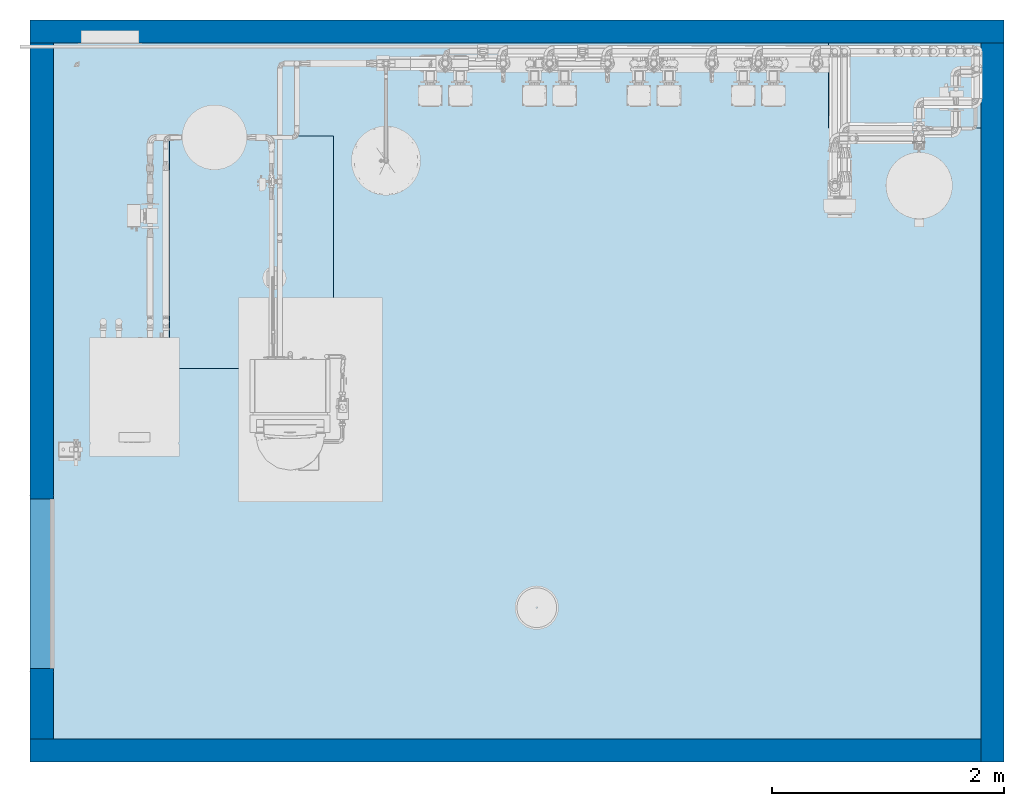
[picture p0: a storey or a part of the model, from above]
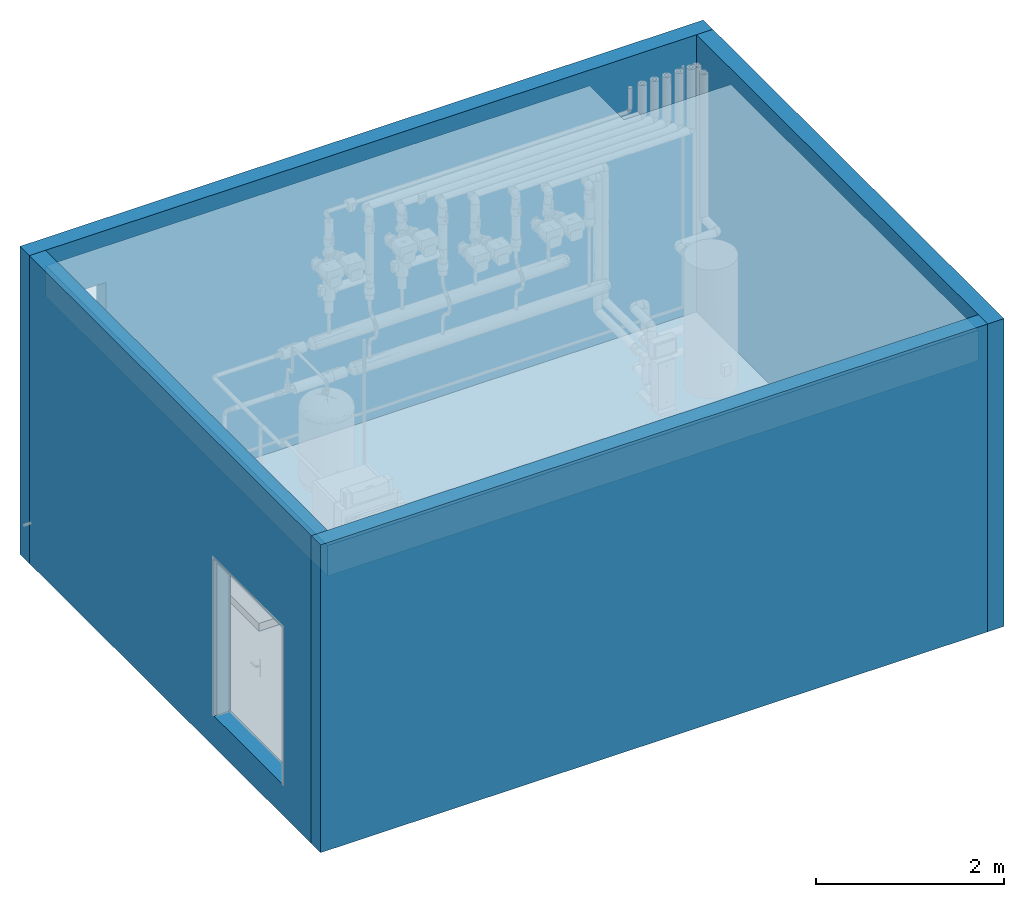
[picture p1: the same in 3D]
Properties of the parts of a building model (IFC2X3)

# File
Description: ViewDefinition [CoordinationView_V2.0], RevitIdentifiers [VersionGUID: c51af800-4d1c-406b-a257-0cf0d2222cb8, NumberOfSaves: 71], CoordinateReference [CoordinateBase: Coordonnées partagées]
File name: 0001
Time: 2023-06-20T16:45:23+01:00
Written by: ODA SDAI 23.12
Made in: Autodesk Revit 24.0.5.432 (FRA) - IFC 24.0.5.432

# IfcProject, 0001
LongName: Chaufferie REVIT MEP; Phase: Etat du projet

# IfcSite, Default
RefLatitude: 48, 51, 23, 807373; RefLongitude: 2, 21, 7, 999076; RefElevation: 0 mm

# IfcBuilding
Pset_BuildingCommon - NumberOfStoreys: 2

# IfcBuildingStorey: Niveau:Pointe 8 mm (2)
Name | LongName | Elevation (mm)
Niveau 0 | Niveau 0 | 0
Niveau 1 | Niveau 1 | 3000

# IfcBuildingElementProxy: Ballon d'eau chaude - 150-300 L test:300 L, Ballon d'eau chaude - 150-300 L test:300 L:723451
In: Niveau 0
Type - Material: <Unnamed>
Pset_BuildingElementProxyCommon - Reference: 300 L; sets with these values: 2
Group: Chauffage aller 2; Chauffage retour 3; Eau Froide Sanitaire 1

# IfcBuildingElementProxy: Collecteurs:Type 1, Collecteurs:Type 1:725838
In: Niveau 0
Type - Material: <Unnamed>
Pset_BuildingElementProxyCommon - Reference: Type 1; sets with these values: 2
Group: Chauffage aller 2; Chauffage aller 4; Chauffage aller 8; Chauffage aller 9; Chauffage aller 1; Chauffage aller 10; Chauffage retour 1; Chauffage aller 11

# IfcBuildingElementProxy: Echangeur de chaleur - Plaques:Standard, Echangeur de chaleur - Plaques:Standard:722448
In: Niveau 0
Type - Material: <Unnamed>
Pset_BuildingElementProxyCommon - Reference: Standard; sets with these values: 2
Group: Chauffage retour 2; Chauffage aller 16; Chauffage aller 2

# IfcBuildingElementProxy: Gaz naturel – Compteur:Compteur gaz G4, Gaz naturel – Compteur:Compteur gaz G4:987432
In: Niveau 0
Type - Material: GRDF Gris, GRDF Blanc, GRDF Jaune, <Unnamed>
Pset_BuildingElementProxyCommon - Reference: Compteur gaz G4; sets with these values: 2
Group: Chauffage retour 7

# IfcBuildingElementProxy: Vase d'expansion:Vase d'expansion, Vase d'expansion:Vase d'expansion:720942
In: Niveau 0
Type - Material: Smooth - Red
Type - Pset_ManufacturerTypeInformation - ArticleNumber: 16301; Manufacturer: Flamco B.V.
Pset_BuildingElementProxyCommon - Reference: Vase d'expansion; sets with these values: 2
Group: Autre 1

# IfcBuildingElementProxy: Viessmann_Vitocal 300-G:BW 301.A29, Viessmann_Vitocal 300-G:BW 301.A29:902832
In: Niveau 0
Type - Material: Color RGB 165-165-165, Color RGB 30-30-30, Color RGB 254-0-0
Type - Pset_ManufacturerTypeInformation - Manufacturer: Viessmann
Type - Pset_ProvisionForVoid - Width: 1086 mm; Height: 1074 mm
Pset_BuildingElementProxyCommon - Reference: BW 301.A29; sets with these values: 2
Group: Chauffage aller 1; Chauffage retour 11; Chauffage aller 5; Chauffage retour 5

# IfcCovering: Isolation des canalisations:Laine minérale (145)
PredefinedType: INSULATION; Material: Isolation - Laine minérale
Pset_CoveringCommon - Reference: Laine minérale; sets with these values: 2
Name (Isolation des canalisations:Laine minérale:...) | In
881231 | Niveau 0
881232 | Niveau 0
881244 | Niveau 0
881245 | Niveau 0
881246 | Niveau 0
881247 | Niveau 0
881248 | Niveau 0
881249 | Niveau 0
881250 | Niveau 0
881251 | Niveau 0
881252 | Niveau 0
881254 | Niveau 0
881255 | Niveau 0
881256 | Niveau 0
881257 | Niveau 0
881258 | Niveau 0
881259 | Niveau 0
881260 | Niveau 0
881261 | Niveau 0
881262 | Niveau 0
881263 | Niveau 0
881264 | Niveau 0
881278 | Niveau 1
881279 | Niveau 1
881280 | Niveau 1
881281 | Niveau 1
881282 | Niveau 1
881283 | Niveau 0
881284 | Niveau 1
881285 | Niveau 0
881286 | Niveau 0
881287 | Niveau 0
881288 | Niveau 1
881297 | Niveau 0
881298 | Niveau 0
881299 | Niveau 0
881300 | Niveau 0
881301 | Niveau 0
881302 | Niveau 0
881304 | Niveau 0
881305 | Niveau 0
881306 | Niveau 0
881307 | Niveau 0
881308 | Niveau 0
881309 | Niveau 0
881310 | Niveau 0
881312 | Niveau 0
881313 | Niveau 0
881320 | Niveau 0
881321 | Niveau 0
881331 | Niveau 0
881332 | Niveau 0
881333 | Niveau 0
881334 | Niveau 0
881335 | Niveau 0
881336 | Niveau 0
881337 | Niveau 0
881338 | Niveau 0
881339 | Niveau 0
881340 | Niveau 0
881341 | Niveau 0
881342 | Niveau 0
881343 | Niveau 0
881344 | Niveau 0
881345 | Niveau 0
881346 | Niveau 0
881347 | Niveau 0
881348 | Niveau 0
881349 | Niveau 0
881350 | Niveau 0
881351 | Niveau 0
881352 | Niveau 0
881353 | Niveau 0
881354 | Niveau 0
881355 | Niveau 0
881356 | Niveau 0
881357 | Niveau 0
881358 | Niveau 0
881359 | Niveau 0
881360 | Niveau 0
881361 | Niveau 0
881362 | Niveau 0
881363 | Niveau 0
881364 | Niveau 0
881365 | Niveau 0
881366 | Niveau 0
881367 | Niveau 0
881368 | Niveau 0
881369 | Niveau 0
881370 | Niveau 0
881371 | Niveau 0
881372 | Niveau 0
881373 | Niveau 0
881374 | Niveau 0
881375 | Niveau 0
881376 | Niveau 0
881377 | Niveau 0
881378 | Niveau 0
881379 | Niveau 0
881380 | Niveau 0
881381 | Niveau 0
881382 | Niveau 0
881383 | Niveau 0
881384 | Niveau 0
881385 | Niveau 0
881386 | Niveau 0
881387 | Niveau 0
881388 | Niveau 0
881389 | Niveau 0
881390 | Niveau 0
881391 | Niveau 0
881392 | Niveau 0
881393 | Niveau 0
881394 | Niveau 0
881395 | Niveau 0
881396 | Niveau 0
881397 | Niveau 0
881398 | Niveau 0
881399 | Niveau 0
881400 | Niveau 0
881401 | Niveau 0
881402 | Niveau 0
881403 | Niveau 0
881404 | Niveau 0
881405 | Niveau 0
881406 | Niveau 0
881409 | Niveau 0
881410 | Niveau 0
881411 | Niveau 0
881412 | Niveau 0
881413 | Niveau 0
881414 | Niveau 0
881434 | Niveau 0
881435 | Niveau 0
881436 | Niveau 0
881437 | Niveau 0
881438 | Niveau 0
881439 | Niveau 0
881440 | Niveau 0
881441 | Niveau 0
881442 | Niveau 0
881443 | Niveau 0
881444 | Niveau 0
881453 | Niveau 0
881454 | Niveau 0

# IfcDistributionPort (621)
Description: Flow
Name | FlowDirection | Group
InPort_720942_1 | SINK | Autre 1
OutPort_934051_2 | SOURCE | Autre 1
InPort_732593_1 | SINK | Chauffage retour 2
OutPort_722448_2 | SOURCE | Chauffage retour 2
InPort_722448_4 | SINK | Chauffage aller 16
OutPort_734984_1 | SOURCE | Chauffage aller 16
Port_722448_5 | SOURCEANDSINK
InPort_836824_1 | SINK | Chauffage aller 16
OutPort_722448_6 | SOURCE | Chauffage aller 16
InPort_722448_7 | SINK | Chauffage aller 2
OutPort_734946_1 | SOURCE | Chauffage aller 2
OutPort_723451_1 | SOURCE
InPort_723451_2 | SINK | Chauffage aller 2
OutPort_825239_0 | SOURCE | Chauffage aller 2
OutPort_723451_3 | SOURCE | Chauffage retour 3
InPort_723451_4 | SINK | Eau Froide Sanitaire 1
OutPort_824245_1 | SOURCE | Eau Froide Sanitaire 1
Port_723451_5 | SOURCEANDSINK
Port_725838_5 | SOURCEANDSINK | Chauffage aller 4
Port_789472_1 | SOURCEANDSINK | Chauffage aller 4
Port_725838_7 | SOURCEANDSINK | Chauffage aller 8
Port_789541_1 | SOURCEANDSINK | Chauffage aller 8
Port_725838_9 | SOURCEANDSINK | Chauffage aller 9
Port_789702_1 | SOURCEANDSINK | Chauffage aller 9
Port_725838_11 | SOURCEANDSINK | Chauffage aller 2
Port_789725_1 | SOURCEANDSINK | Chauffage aller 2
InPort_725838_13 | SINK | Chauffage aller 1
OutPort_813002_0 | SOURCE | Chauffage aller 1
Port_725838_14 | SOURCEANDSINK | Chauffage aller 4
Port_731198_1 | SOURCEANDSINK | Chauffage aller 4
Port_725838_15 | SOURCEANDSINK | Chauffage aller 8
Port_788116_1 | SOURCEANDSINK | Chauffage aller 8
Port_725838_16 | SOURCEANDSINK | Chauffage aller 10
Port_731342_1 | SOURCEANDSINK | Chauffage aller 10
InPort_725838_18 | SINK | Chauffage retour 1
OutPort_812962_0 | SOURCE | Chauffage retour 1
InPort_731486_1 | SINK | Chauffage aller 11
OutPort_725838_19 | SOURCE | Chauffage aller 11
Port_730939_0 | SOURCEANDSINK | Chauffage aller 12
Port_777958_1 | SOURCEANDSINK | Chauffage aller 12
Port_730939_1 | SOURCEANDSINK | Chauffage aller 12
Port_732698_2 | SOURCEANDSINK | Chauffage aller 12
Port_730962_0 | SOURCEANDSINK | Chauffage aller 12
Port_880787_2 | SOURCEANDSINK | Chauffage aller 12
Port_730962_1 | SOURCEANDSINK | Chauffage aller 12
Port_732700_2 | SOURCEANDSINK | Chauffage aller 12
Port_731057_0 | SOURCEANDSINK | Chauffage aller 12
Port_732700_1 | SOURCEANDSINK | Chauffage aller 12
Port_731057_1 | SOURCEANDSINK | Chauffage aller 12
Port_731196_0 | SOURCEANDSINK | Chauffage aller 4
Port_784621_1 | SOURCEANDSINK | Chauffage aller 4
Port_731196_1 | SOURCEANDSINK | Chauffage aller 4
Port_731204_2 | SOURCEANDSINK | Chauffage aller 4
Port_731198_0 | SOURCEANDSINK | Chauffage aller 4
Port_877798_1 | SOURCEANDSINK | Chauffage aller 4
Port_731202_0 | SOURCEANDSINK | Chauffage aller 4
Port_731204_1 | SOURCEANDSINK | Chauffage aller 4
Port_731202_1 | SOURCEANDSINK | Chauffage aller 4
Port_731210_1 | SOURCEANDSINK | Chauffage aller 4
Port_731208_0 | SOURCEANDSINK | Chauffage aller 4
Port_731210_2 | SOURCEANDSINK | Chauffage aller 4
Port_731208_1 | SOURCEANDSINK | Chauffage aller 4
Port_731294_0 | SOURCEANDSINK | Chauffage aller 13
Port_788303_1 | SOURCEANDSINK | Chauffage aller 13
Port_731294_1 | SOURCEANDSINK | Chauffage aller 13
Port_731651_2 | SOURCEANDSINK | Chauffage aller 13
Port_731300_0 | SOURCEANDSINK | Chauffage aller 13
Port_880819_2 | SOURCEANDSINK | Chauffage aller 13
Port_731300_1 | SOURCEANDSINK | Chauffage aller 13
Port_731653_2 | SOURCEANDSINK | Chauffage aller 13
Port_731318_0 | SOURCEANDSINK | Chauffage aller 8
Port_788230_1 | SOURCEANDSINK | Chauffage aller 8
Port_731318_1 | SOURCEANDSINK | Chauffage aller 8
Port_731695_2 | SOURCEANDSINK | Chauffage aller 8
Port_731324_0 | SOURCEANDSINK | Chauffage aller 8
Port_731695_1 | SOURCEANDSINK | Chauffage aller 8
Port_731324_1 | SOURCEANDSINK | Chauffage aller 8
Port_731697_2 | SOURCEANDSINK | Chauffage aller 8
Port_731340_0 | SOURCEANDSINK | Chauffage aller 10
Port_791255_1 | SOURCEANDSINK | Chauffage aller 10
Port_731340_1 | SOURCEANDSINK | Chauffage aller 10
Port_731843_2 | SOURCEANDSINK | Chauffage aller 10
Port_731342_0 | SOURCEANDSINK | Chauffage aller 10
Port_877814_1 | SOURCEANDSINK | Chauffage aller 10
Port_731346_0 | SOURCEANDSINK | Chauffage aller 10
Port_731843_1 | SOURCEANDSINK | Chauffage aller 10
Port_731346_1 | SOURCEANDSINK | Chauffage aller 10
Port_731845_2 | SOURCEANDSINK | Chauffage aller 10
Port_731430_0 | SOURCEANDSINK | Chauffage aller 14
Port_788510_1 | SOURCEANDSINK | Chauffage aller 14
Port_731430_1 | SOURCEANDSINK | Chauffage aller 14
Port_731759_2 | SOURCEANDSINK | Chauffage aller 14
Port_731436_0 | SOURCEANDSINK | Chauffage aller 14
Port_731759_1 | SOURCEANDSINK | Chauffage aller 14
Port_731436_1 | SOURCEANDSINK | Chauffage aller 14
Port_731761_2 | SOURCEANDSINK | Chauffage aller 14
InPort_731458_0 | SINK | Chauffage aller 2
OutPort_789825_1 | SOURCE | Chauffage aller 2
InPort_731466_2 | SINK | Chauffage aller 2
OutPort_731458_1 | SOURCE | Chauffage aller 2
InPort_800652_1 | SINK | Chauffage aller 2
OutPort_731460_0 | SOURCE | Chauffage aller 2
InPort_731460_1 | SINK | Chauffage aller 2
InPort_732428_0 | SINK | Chauffage aller 2
OutPort_731466_1 | SOURCE | Chauffage aller 2
InPort_731484_0 | SINK | Chauffage aller 11
OutPort_791313_1 | SOURCE | Chauffage aller 11
InPort_731492_2 | SINK | Chauffage aller 11
OutPort_731484_1 | SOURCE | Chauffage aller 11
InPort_877834_1 | SINK | Chauffage aller 11
OutPort_731486_0 | SOURCE | Chauffage aller 11
InPort_732634_0 | SINK | Chauffage aller 11
OutPort_731492_1 | SOURCE | Chauffage aller 11
Port_731572_0 | SOURCEANDSINK | Chauffage aller 13
Port_731653_1 | SOURCEANDSINK | Chauffage aller 13
Port_731572_1 | SOURCEANDSINK | Chauffage aller 13
Port_731586_0 | SOURCEANDSINK | Chauffage aller 8
Port_731697_1 | SOURCEANDSINK | Chauffage aller 8
Port_731586_1 | SOURCEANDSINK | Chauffage aller 8
Port_731600_0 | SOURCEANDSINK | Chauffage aller 14
Port_731761_1 | SOURCEANDSINK | Chauffage aller 14
Port_731600_1 | SOURCEANDSINK | Chauffage aller 14
Port_731651_1 | SOURCEANDSINK | Chauffage aller 13
Port_880821_0 | SOURCEANDSINK | Chauffage aller 13
Port_731790_0 | SOURCEANDSINK | Chauffage aller 10
Port_731845_1 | SOURCEANDSINK | Chauffage aller 10
Port_731790_1 | SOURCEANDSINK | Chauffage aller 10
InPort_734948_1 | SINK | Chauffage aller 2
OutPort_732251_0 | SOURCE | Chauffage aller 2
InPort_732251_1 | SINK | Chauffage aller 2
OutPort_732496_2 | SOURCE | Chauffage aller 2
InPort_732496_1 | SINK | Chauffage aller 2
OutPort_732428_1 | SOURCE | Chauffage aller 2
InPort_732518_0 | SINK | Chauffage retour 2
OutPort_732593_2 | SOURCE | Chauffage retour 2
InPort_809786_1 | SINK | Chauffage retour 2
OutPort_732518_1 | SOURCE | Chauffage retour 2
InPort_809790_1 | SINK | Chauffage aller 11
OutPort_732634_1 | SOURCE | Chauffage aller 11
Port_732698_1 | SOURCEANDSINK | Chauffage aller 12
Port_880789_0 | SOURCEANDSINK | Chauffage aller 12
Port_734033_0 | SOURCEANDSINK | Chauffage aller 16
Port_836876_3 | SOURCEANDSINK | Chauffage aller 16
Port_734033_1 | SOURCEANDSINK | Chauffage aller 16
Port_836287_3 | SOURCEANDSINK | Chauffage aller 16
InPort_734276_0 | SINK | Chauffage retour 4
OutPort_824275_2 | SOURCE | Chauffage retour 4
InPort_824307_2 | SINK | Eau Froide Sanitaire 1
OutPort_734276_1 | SOURCE | Eau Froide Sanitaire 1
Port_734457_0 | SOURCEANDSINK | Autre 1
Port_934110_2 | SOURCEANDSINK | Autre 1
Port_734457_1 | SOURCEANDSINK | Autre 1
Port_934114_2 | SOURCEANDSINK | Autre 1
Port_734536_0 | SOURCEANDSINK | Autre 1
Port_934110_1 | SOURCEANDSINK | Autre 1
Port_734536_1 | SOURCEANDSINK | Autre 1
Port_789916_1 | SOURCEANDSINK | Autre 1
Port_734538_1 | SOURCEANDSINK | Chauffage retour 1
InPort_734539_1 | SINK | Chauffage retour 1
OutPort_734538_2 | SOURCE | Chauffage retour 1
InPort_734538_3 | SINK | Chauffage retour 1
OutPort_869441_1 | SOURCE | Chauffage retour 1
InPort_812960_1 | SINK | Chauffage retour 1
OutPort_734539_0 | SOURCE | Chauffage retour 1
InPort_734986_1 | SINK | Chauffage aller 16
OutPort_734875_0 | SOURCE | Chauffage aller 16
InPort_734875_1 | SINK | Chauffage aller 16
OutPort_836876_1 | SOURCE | Chauffage aller 16
InPort_734946_2 | SINK | Chauffage aller 2
OutPort_734887_0 | SOURCE | Chauffage aller 2
InPort_734887_1 | SINK | Chauffage aller 2
OutPort_734948_2 | SOURCE | Chauffage aller 2
InPort_734984_2 | SINK | Chauffage aller 16
OutPort_734972_0 | SOURCE | Chauffage aller 16
InPort_734972_1 | SINK | Chauffage aller 16
OutPort_734986_2 | SOURCE | Chauffage aller 16
Port_761970_4 | SOURCEANDSINK | Chauffage aller 4
Port_789420_1 | SOURCEANDSINK | Chauffage aller 4
Port_761970_5 | SOURCEANDSINK
Port_761970_6 | SOURCEANDSINK
Port_761970_7 | SOURCEANDSINK | Chauffage aller 4
Port_761970_8 | SOURCEANDSINK | Chauffage aller 4
Port_777889_0 | SOURCEANDSINK | Chauffage aller 12
Port_800542_2 | SOURCEANDSINK | Chauffage aller 12
Port_777889_1 | SOURCEANDSINK | Chauffage aller 12
Port_777958_2 | SOURCEANDSINK | Chauffage aller 12
Port_784621_2 | SOURCEANDSINK | Chauffage aller 4
Port_800558_0 | SOURCEANDSINK | Chauffage aller 4
Port_784664_1 | SOURCEANDSINK | Chauffage aller 4
Port_789472_0 | SOURCEANDSINK | Chauffage aller 4
Port_784664_2 | SOURCEANDSINK | Chauffage aller 4
Port_789420_0 | SOURCEANDSINK | Chauffage aller 4
InPort_788051_1 | SINK | Chauffage aller 4
OutPort_784664_3 | SOURCE | Chauffage aller 4
Port_784664_4 | SOURCEANDSINK
InPort_788062_3 | SINK | Chauffage aller 4
OutPort_788051_0 | SOURCE | Chauffage aller 4
Port_788062_1 | SOURCEANDSINK | Chauffage aller 4
Port_877800_0 | SOURCEANDSINK | Chauffage aller 4
Port_788062_2 | SOURCEANDSINK | Chauffage aller 4
Port_788063_1 | SOURCEANDSINK | Chauffage aller 4
Port_788063_0 | SOURCEANDSINK | Chauffage aller 4
Port_800556_1 | SOURCEANDSINK | Chauffage aller 4
Port_788116_0 | SOURCEANDSINK | Chauffage aller 8
Port_877776_1 | SOURCEANDSINK | Chauffage aller 8
Port_788118_4 | SOURCEANDSINK | Chauffage aller 8
Port_825383_0 | SOURCEANDSINK | Chauffage aller 8
Port_788118_5 | SOURCEANDSINK
Port_788118_6 | SOURCEANDSINK
Port_788118_7 | SOURCEANDSINK | Chauffage aller 8
Port_788118_8 | SOURCEANDSINK | Chauffage aller 8
Port_788121_0 | SOURCEANDSINK | Chauffage aller 13
Port_800572_2 | SOURCEANDSINK | Chauffage aller 13
Port_788121_1 | SOURCEANDSINK | Chauffage aller 13
Port_788303_2 | SOURCEANDSINK | Chauffage aller 13
Port_788127_1 | SOURCEANDSINK | Chauffage aller 8
Port_789541_0 | SOURCEANDSINK | Chauffage aller 8
Port_788127_2 | SOURCEANDSINK | Chauffage aller 8
Port_825383_1 | SOURCEANDSINK | Chauffage aller 8
InPort_788132_1 | SINK | Chauffage aller 8
OutPort_788127_3 | SOURCE | Chauffage aller 8
Port_788127_4 | SOURCEANDSINK
InPort_788134_3 | SINK | Chauffage aller 8
OutPort_788132_0 | SOURCE | Chauffage aller 8
Port_788134_1 | SOURCEANDSINK | Chauffage aller 8
Port_877778_0 | SOURCEANDSINK | Chauffage aller 8
Port_788134_2 | SOURCEANDSINK | Chauffage aller 8
Port_825423_1 | SOURCEANDSINK | Chauffage aller 8
Port_788135_0 | SOURCEANDSINK | Chauffage aller 8
Port_800588_2 | SOURCEANDSINK | Chauffage aller 8
Port_788135_1 | SOURCEANDSINK | Chauffage aller 8
Port_788230_2 | SOURCEANDSINK | Chauffage aller 8
Port_788332_4 | SOURCEANDSINK | Chauffage aller 9
Port_789702_0 | SOURCEANDSINK | Chauffage aller 9
Port_788332_5 | SOURCEANDSINK
Port_788332_6 | SOURCEANDSINK
Port_788332_7 | SOURCEANDSINK | Chauffage aller 9
Port_788332_8 | SOURCEANDSINK | Chauffage aller 9
Port_788391_4 | SOURCEANDSINK | Chauffage aller 2
Port_789725_0 | SOURCEANDSINK | Chauffage aller 2
Port_788391_5 | SOURCEANDSINK
Port_788391_6 | SOURCEANDSINK
Port_788391_7 | SOURCEANDSINK | Chauffage aller 2
Port_788391_8 | SOURCEANDSINK | Chauffage aller 2
Port_788456_0 | SOURCEANDSINK | Chauffage aller 14
Port_800612_1 | SOURCEANDSINK | Chauffage aller 14
Port_788456_1 | SOURCEANDSINK | Chauffage aller 14
Port_788510_2 | SOURCEANDSINK | Chauffage aller 14
Port_800614_0 | SOURCEANDSINK | Chauffage aller 14
InPort_789825_2 | SINK | Chauffage aller 2
OutPort_800654_0 | SOURCE | Chauffage aller 2
InPort_869441_2 | SINK | Chauffage retour 1
OutPort_789910_0 | SOURCE | Chauffage retour 1
Port_789910_1 | SOURCEANDSINK | Autre 1
Port_869536_2 | SOURCEANDSINK | Autre 1
Port_789916_2 | SOURCEANDSINK | Autre 1
Port_869520_0 | SOURCEANDSINK | Autre 1
Port_791255_2 | SOURCEANDSINK | Chauffage aller 10
Port_800630_0 | SOURCEANDSINK | Chauffage aller 10
InPort_791313_2 | SINK | Chauffage aller 11
OutPort_800675_0 | SOURCE | Chauffage aller 11
Port_800542_1 | SOURCEANDSINK | Chauffage aller 12
Port_800544_1 | SOURCEANDSINK | Chauffage aller 12
Port_800544_0 | SOURCEANDSINK | Chauffage aller 12
Port_800556_2 | SOURCEANDSINK | Chauffage aller 4
Port_800558_1 | SOURCEANDSINK | Chauffage aller 4
Port_800572_1 | SOURCEANDSINK | Chauffage aller 13
Port_800574_1 | SOURCEANDSINK | Chauffage aller 13
Port_800574_0 | SOURCEANDSINK | Chauffage aller 13
Port_800588_1 | SOURCEANDSINK | Chauffage aller 8
Port_825423_0 | SOURCEANDSINK | Chauffage aller 8
Port_800612_2 | SOURCEANDSINK | Chauffage aller 14
Port_800614_1 | SOURCEANDSINK | Chauffage aller 14
Port_800628_1 | SOURCEANDSINK | Chauffage aller 10
Port_877816_0 | SOURCEANDSINK | Chauffage aller 10
Port_800628_2 | SOURCEANDSINK | Chauffage aller 10
Port_800630_1 | SOURCEANDSINK | Chauffage aller 10
InPort_800654_1 | SINK | Chauffage aller 2
OutPort_800652_2 | SOURCE | Chauffage aller 2
InPort_800673_1 | SINK | Chauffage aller 11
OutPort_877836_0 | SOURCE | Chauffage aller 11
InPort_800675_1 | SINK | Chauffage aller 11
OutPort_800673_2 | SOURCE | Chauffage aller 11
InPort_806821_0 | SINK | Chauffage retour 2
OutPort_809786_2 | SOURCE | Chauffage retour 2
InPort_806821_1 | SINK | Chauffage retour 2
OutPort_809790_2 | SOURCE | Chauffage retour 2
InPort_812962_1 | SINK | Chauffage retour 1
OutPort_812960_2 | SOURCE | Chauffage retour 1
InPort_813000_1 | SINK | Chauffage aller 1
OutPort_933412_1 | SOURCE | Chauffage aller 1
InPort_813002_1 | SINK | Chauffage aller 1
OutPort_813000_2 | SOURCE | Chauffage aller 1
InPort_824020_0 | SINK | Chauffage aller 16
OutPort_836824_2 | SOURCE | Chauffage aller 16
InPort_836860_2 | SINK | Chauffage aller 16
OutPort_824020_1 | SOURCE | Chauffage aller 16
InPort_824245_2 | SINK | Eau Froide Sanitaire 1
OutPort_824278_0 | SOURCE | Eau Froide Sanitaire 1
InPort_824275_1 | SINK | Chauffage aller 16
OutPort_836562_0 | SOURCE | Chauffage aller 16
InPort_824278_1 | SINK | Eau Froide Sanitaire 1
OutPort_824307_1 | SOURCE | Eau Froide Sanitaire 1
Port_824420_0 | SOURCEANDSINK | Chauffage aller 18
Port_836287_1 | SOURCEANDSINK | Chauffage aller 18
Port_824420_1 | SOURCEANDSINK | Chauffage aller 18
Port_824445_0 | SOURCEANDSINK | Chauffage aller 18
Port_824453_1 | SOURCEANDSINK | Chauffage aller 18
Port_824445_1 | SOURCEANDSINK | Chauffage aller 18
Port_824805_1 | SOURCEANDSINK | Chauffage aller 18
Port_824453_2 | SOURCEANDSINK | Chauffage aller 18
Port_836289_0 | SOURCEANDSINK | Chauffage aller 18
Port_824455_0 | SOURCEANDSINK | Chauffage aller 18
Port_824502_1 | SOURCEANDSINK | Chauffage aller 18
Port_824455_1 | SOURCEANDSINK | Chauffage aller 18
Port_824805_2 | SOURCEANDSINK | Chauffage aller 18
Port_824502_2 | SOURCEANDSINK | Chauffage aller 18
Port_824640_0 | SOURCEANDSINK | Chauffage aller 15
Port_824640_1 | SOURCEANDSINK | Chauffage aller 15
Port_824673_0 | SOURCEANDSINK | Chauffage aller 17
Port_825222_2 | SOURCEANDSINK | Chauffage aller 17
Port_824673_1 | SOURCEANDSINK | Chauffage aller 17
Port_831752_2 | SOURCEANDSINK | Chauffage aller 17
Port_824677_0 | SOURCEANDSINK | Chauffage aller 17
Port_825222_1 | SOURCEANDSINK | Chauffage aller 17
Port_824677_1 | SOURCEANDSINK | Chauffage aller 17
InPort_825249_1 | SINK | Chauffage aller 2
OutPort_824781_0 | SOURCE | Chauffage aller 2
InPort_824781_1 | SINK | Chauffage aller 2
OutPort_853764_1 | SOURCE | Chauffage aller 2
InPort_825239_1 | SINK | Chauffage aller 2
OutPort_825249_2 | SOURCE | Chauffage aller 2
Port_831752_1 | SOURCEANDSINK | Chauffage aller 17
Port_831779_0 | SOURCEANDSINK | Chauffage aller 17
Port_831779_1 | SOURCEANDSINK | Chauffage aller 17
Port_831797_1 | SOURCEANDSINK | Chauffage aller 17
Port_831797_2 | SOURCEANDSINK | Chauffage aller 17
Port_836287_2 | SOURCEANDSINK | Chauffage aller 18
Port_836289_1 | SOURCEANDSINK | Chauffage aller 18
InPort_836562_1 | SINK | Chauffage aller 16
OutPort_836610_1 | SOURCE | Chauffage aller 16
InPort_836668_2 | SINK | Chauffage aller 16
OutPort_836570_0 | SOURCE | Chauffage aller 16
InPort_836570_1 | SINK | Chauffage aller 16
OutPort_836702_1 | SOURCE | Chauffage aller 16
InPort_836610_2 | SINK | Chauffage aller 16
OutPort_836608_0 | SOURCE | Chauffage aller 16
InPort_836608_1 | SINK | Chauffage aller 16
OutPort_836668_1 | SOURCE | Chauffage aller 16
InPort_836702_2 | SINK | Chauffage aller 16
OutPort_836827_0 | SOURCE | Chauffage aller 16
InPort_836827_1 | SINK | Chauffage aller 16
OutPort_836860_1 | SOURCE | Chauffage aller 16
Port_836876_2 | SOURCEANDSINK | Chauffage aller 16
Port_836971_1 | SOURCEANDSINK | Chauffage aller 16
Port_836907_0 | SOURCEANDSINK | Chauffage aller 16
Port_836971_2 | SOURCEANDSINK | Chauffage aller 16
Port_836907_1 | SOURCEANDSINK | Chauffage aller 16
Port_836927_1 | SOURCEANDSINK | Chauffage aller 16
Port_836917_0 | SOURCEANDSINK | Chauffage aller 16
Port_836927_2 | SOURCEANDSINK | Chauffage aller 16
Port_836917_1 | SOURCEANDSINK | Chauffage aller 16
Port_836937_1 | SOURCEANDSINK | Chauffage aller 16
Port_836937_2 | SOURCEANDSINK | Chauffage aller 16
Port_837179_0 | SOURCEANDSINK | Chauffage aller 16
Port_837075_0 | SOURCEANDSINK | Chauffage aller 16
Port_837075_1 | SOURCEANDSINK | Chauffage aller 16
Port_837166_1 | SOURCEANDSINK | Chauffage aller 16
Port_837131_0 | SOURCEANDSINK | Chauffage aller 16
Port_837166_3 | SOURCEANDSINK | Chauffage aller 16
Port_837131_1 | SOURCEANDSINK | Chauffage aller 16
Port_837166_2 | SOURCEANDSINK | Chauffage aller 16
Port_837179_1 | SOURCEANDSINK | Chauffage aller 16
Port_853629_1 | SOURCEANDSINK | Chauffage aller 19
Port_853629_2 | SOURCEANDSINK | Chauffage aller 19
InPort_853764_2 | SINK | Chauffage aller 2
Port_853877_2 | SOURCEANDSINK | Chauffage aller 20
Port_853978_0 | SOURCEANDSINK | Chauffage aller 20
Port_853877_4 | SOURCEANDSINK | Chauffage aller 20
Port_854038_0 | SOURCEANDSINK | Chauffage aller 20
Port_853877_5 | SOURCEANDSINK
Port_853978_1 | SOURCEANDSINK | Chauffage aller 20
Port_854038_1 | SOURCEANDSINK | Chauffage aller 20
Port_869520_1 | SOURCEANDSINK | Autre 1
Port_869536_1 | SOURCEANDSINK | Autre 1
Port_872736_1 | SOURCEANDSINK | Eaux Usées 2
Port_872736_2 | SOURCEANDSINK | Eaux Usées 2
OutPort_874839_1 | SOURCE
Port_877776_2 | SOURCEANDSINK | Chauffage aller 8
Port_877778_1 | SOURCEANDSINK | Chauffage aller 8
Port_877798_2 | SOURCEANDSINK | Chauffage aller 4
Port_877800_1 | SOURCEANDSINK | Chauffage aller 4
Port_877814_2 | SOURCEANDSINK | Chauffage aller 10
Port_877816_1 | SOURCEANDSINK | Chauffage aller 10
InPort_877836_1 | SINK | Chauffage aller 11
OutPort_877834_2 | SOURCE | Chauffage aller 11
Port_880787_1 | SOURCEANDSINK | Chauffage aller 12
Port_880789_1 | SOURCEANDSINK | Chauffage aller 12
Port_880819_1 | SOURCEANDSINK | Chauffage aller 13
Port_880821_1 | SOURCEANDSINK | Chauffage aller 13
Port_883311_1 | SOURCEANDSINK
InPort_902832_1 | SINK | Chauffage retour 11
OutPort_992128_0 | SOURCE | Chauffage retour 11
InPort_991940_0 | SINK | Chauffage aller 5
OutPort_902832_2 | SOURCE | Chauffage aller 5
InPort_931899_0 | SINK | Chauffage aller 1
OutPort_902832_3 | SOURCE | Chauffage aller 1
InPort_902832_4 | SINK | Chauffage retour 5
OutPort_932032_0 | SOURCE | Chauffage retour 5
Port_902832_5 | SOURCEANDSINK
Port_902832_6 | SOURCEANDSINK
InPort_911631_1 | SINK | Chauffage aller 3
InPort_911885_0 | SINK | Chauffage aller 3
OutPort_911631_2 | SOURCE | Chauffage aller 3
InPort_933680_1 | SINK | Chauffage aller 3
OutPort_911885_1 | SOURCE | Chauffage aller 3
Port_913983_1 | SOURCEANDSINK | Chauffage retour 10
Port_989369_0 | SOURCEANDSINK | Chauffage retour 10
Port_913983_2 | SOURCEANDSINK | Chauffage retour 10
Port_913983_3 | SOURCEANDSINK | Chauffage retour 10
InPort_913983_4 | SINK | Chauffage retour 10
OutPort_993150_0 | SOURCE | Chauffage retour 10
Port_913983_5 | SOURCEANDSINK | Chauffage retour 10
Port_913983_6 | SOURCEANDSINK | Chauffage retour 6
Port_932527_0 | SOURCEANDSINK | Chauffage retour 6
Port_913983_7 | SOURCEANDSINK | Chauffage retour 10
Port_913983_8 | SOURCEANDSINK | Chauffage retour 10
Port_913983_9 | SOURCEANDSINK | Chauffage aller 1
Port_918356_0 | SOURCEANDSINK | Chauffage aller 1
Port_913983_10 | SOURCEANDSINK | Chauffage retour 10
InPort_918343_0 | SINK | Chauffage aller 1
OutPort_932846_1 | SOURCE | Chauffage aller 1
InPort_933415_2 | SINK | Chauffage aller 1
OutPort_918343_1 | SOURCE | Chauffage aller 1
InPort_918356_0 | SINK | Chauffage aller 1
OutPort_913983_9 | SOURCE | Chauffage aller 1
InPort_918360_1 | SINK | Chauffage aller 1
OutPort_918356_1 | SOURCE | Chauffage aller 1
InPort_918357_0 | SINK | Chauffage aller 1
OutPort_918360_2 | SOURCE | Chauffage aller 1
InPort_918364_1 | SINK | Chauffage aller 1
OutPort_918357_1 | SOURCE | Chauffage aller 1
InPort_932849_0 | SINK | Chauffage aller 1
OutPort_918364_2 | SOURCE | Chauffage aller 1
InPort_933412_2 | SINK | Chauffage aller 1
OutPort_918368_0 | SOURCE | Chauffage aller 1
InPort_918368_1 | SINK | Chauffage aller 1
OutPort_933415_1 | SOURCE | Chauffage aller 1
InPort_931176_5 | SINK | Chauffage aller 1
OutPort_931925_1 | SOURCE | Chauffage aller 1
Port_931176_6 | SOURCEANDSINK
Port_931176_7 | SOURCEANDSINK
InPort_932222_0 | SINK | Chauffage retour 5
OutPort_931176_8 | SOURCE | Chauffage retour 5
Port_931176_9 | SOURCEANDSINK
InPort_932395_1 | SINK | Chauffage retour 6
OutPort_931176_10 | SOURCE | Chauffage retour 6
Port_931176_11 | SOURCEANDSINK
Port_931176_12 | SOURCEANDSINK
InPort_931176_13 | SINK | Chauffage retour 9
OutPort_933669_0 | SOURCE | Chauffage retour 9
InPort_931886_0 | SINK | Chauffage aller 1
OutPort_981580_1 | SOURCE | Chauffage aller 1
InPort_931927_2 | SINK | Chauffage aller 1
OutPort_931886_1 | SOURCE | Chauffage aller 1
InPort_931903_1 | SINK | Chauffage aller 1
OutPort_931899_1 | SOURCE | Chauffage aller 1
InPort_931900_0 | SINK | Chauffage aller 1
OutPort_931903_2 | SOURCE | Chauffage aller 1
InPort_931907_1 | SINK | Chauffage aller 1
OutPort_931900_1 | SOURCE | Chauffage aller 1
InPort_981417_0 | SINK | Chauffage aller 1
OutPort_931907_2 | SOURCE | Chauffage aller 1
InPort_931925_2 | SINK | Chauffage aller 1
OutPort_931911_0 | SOURCE | Chauffage aller 1
InPort_931911_1 | SINK | Chauffage aller 1
OutPort_931927_1 | SOURCE | Chauffage aller 1
InPort_932181_2 | SINK | Chauffage retour 5
OutPort_932019_0 | SOURCE | Chauffage retour 5
InPort_932019_1 | SINK | Chauffage retour 5
OutPort_932230_1 | SOURCE | Chauffage retour 5
InPort_932032_1 | SINK | Chauffage retour 5
OutPort_932036_1 | SOURCE | Chauffage retour 5
InPort_932036_2 | SINK | Chauffage retour 5
OutPort_932033_0 | SOURCE | Chauffage retour 5
InPort_932033_1 | SINK | Chauffage retour 5
OutPort_932181_1 | SOURCE | Chauffage retour 5
InPort_932230_2 | SINK | Chauffage retour 5
OutPort_932209_0 | SOURCE | Chauffage retour 5
InPort_932209_1 | SINK | Chauffage retour 5
OutPort_932235_2 | SOURCE | Chauffage retour 5
InPort_932233_1 | SINK | Chauffage retour 5
OutPort_932222_1 | SOURCE | Chauffage retour 5
InPort_932235_1 | SINK | Chauffage retour 5
OutPort_932233_2 | SOURCE | Chauffage retour 5
InPort_932373_0 | SINK | Chauffage retour 6
OutPort_932395_2 | SOURCE | Chauffage retour 6
InPort_937511_2 | SINK | Chauffage retour 6
OutPort_932373_1 | SOURCE | Chauffage retour 6
InPort_932532_1 | SINK | Chauffage retour 6
OutPort_932385_0 | SOURCE | Chauffage retour 6
InPort_932385_1 | SINK | Chauffage retour 6
OutPort_933796_2 | SOURCE | Chauffage retour 6
InPort_932503_1 | SINK | Chauffage retour 6
OutPort_932532_2 | SOURCE | Chauffage retour 6
InPort_932503_2 | SINK | Chauffage retour 6
OutPort_932529_2 | SOURCE | Chauffage retour 6
OutPort_932503_3 | SOURCE | Chauffage retour 6
Port_932503_4 | SOURCEANDSINK
InPort_932527_0 | SINK | Chauffage retour 6
OutPort_913983_6 | SOURCE | Chauffage retour 6
InPort_932529_1 | SINK | Chauffage retour 6
OutPort_932527_1 | SOURCE | Chauffage retour 6
InPort_932846_2 | SINK | Chauffage aller 1
OutPort_932849_1 | SOURCE | Chauffage aller 1
InPort_933294_1 | SINK | Chauffage aller 1
OutPort_932846_3 | SOURCE | Chauffage aller 1
InPort_933275_0 | SINK | Chauffage retour 8
OutPort_933294_2 | SOURCE | Chauffage retour 8
InPort_933277_1 | SINK | Chauffage retour 8
OutPort_933275_1 | SOURCE | Chauffage retour 8
OutPort_933277_2 | SOURCE | Chauffage retour 8
InPort_933656_0 | SINK | Chauffage retour 9
OutPort_933682_2 | SOURCE | Chauffage retour 9
InPort_933688_2 | SINK | Chauffage retour 9
OutPort_933656_1 | SOURCE | Chauffage retour 9
InPort_933669_1 | SINK | Chauffage retour 9
OutPort_933686_1 | SOURCE | Chauffage retour 9
InPort_933676_0 | SINK | Chauffage retour 9
OutPort_933678_2 | SOURCE | Chauffage retour 9
InPort_933682_1 | SINK | Chauffage retour 9
OutPort_933676_1 | SOURCE | Chauffage retour 9
InPort_933678_1 | SINK | Chauffage aller 3
OutPort_933680_2 | SOURCE | Chauffage aller 3
InPort_933686_2 | SINK | Chauffage retour 9
OutPort_933688_1 | SOURCE | Chauffage retour 9
InPort_933796_1 | SINK | Chauffage retour 6
OutPort_937511_1 | SOURCE | Chauffage retour 6
Port_934051_1 | SOURCEANDSINK | Autre 1
Port_934114_1 | SOURCEANDSINK | Autre 1
Port_934116_2 | SOURCEANDSINK | Autre 1
Port_934116_1 | SOURCEANDSINK | Autre 1
Port_937416_1 | SOURCEANDSINK | Autre 1
InPort_937416_1 | SINK | Autre 1
OutPort_934116_1 | SOURCE | Autre 1
OutPort_937416_2 | SOURCE | Autre 1
InPort_981415_1 | SINK | Chauffage aller 1
OutPort_981419_2 | SOURCE | Chauffage aller 1
InPort_981421_2 | SINK | Chauffage aller 1
OutPort_981415_2 | SOURCE | Chauffage aller 1
Port_981415_3 | SOURCEANDSINK
InPort_981419_1 | SINK | Chauffage aller 1
OutPort_981417_1 | SOURCE | Chauffage aller 1
InPort_981576_0 | SINK | Chauffage aller 1
OutPort_981421_1 | SOURCE | Chauffage aller 1
InPort_981580_2 | SINK | Chauffage aller 1
OutPort_981548_1 | SOURCE | Chauffage aller 1
InPort_981548_2 | SINK | Chauffage aller 1
OutPort_981578_2 | SOURCE | Chauffage aller 1
InPort_981578_1 | SINK | Chauffage aller 1
OutPort_981576_1 | SOURCE | Chauffage aller 1
Port_984671_1 | SOURCEANDSINK | Chauffage retour 10
Port_985187_0 | SOURCEANDSINK | Chauffage retour 10
Port_984671_2 | SOURCEANDSINK | Chauffage retour 10
Port_988024_0 | SOURCEANDSINK | Chauffage retour 10
Port_985168_0 | SOURCEANDSINK | Chauffage retour 10
Port_985195_2 | SOURCEANDSINK | Chauffage retour 10
Port_985168_1 | SOURCEANDSINK | Chauffage retour 10
Port_985199_2 | SOURCEANDSINK | Chauffage retour 10
Port_985179_0 | SOURCEANDSINK | Chauffage retour 10
Port_989356_2 | SOURCEANDSINK | Chauffage retour 10
Port_985179_1 | SOURCEANDSINK | Chauffage retour 10
Port_985199_1 | SOURCEANDSINK | Chauffage retour 10
Port_985187_1 | SOURCEANDSINK | Chauffage retour 10
Port_985193_1 | SOURCEANDSINK | Chauffage retour 10
Port_985188_0 | SOURCEANDSINK | Chauffage retour 10
Port_985191_2 | SOURCEANDSINK | Chauffage retour 10
Port_985188_1 | SOURCEANDSINK | Chauffage retour 10
Port_985195_1 | SOURCEANDSINK | Chauffage retour 10
Port_985191_1 | SOURCEANDSINK | Chauffage retour 10
Port_985193_2 | SOURCEANDSINK | Chauffage retour 10
Port_987432_1 | SOURCEANDSINK | Chauffage retour 7
Port_987432_2 | SOURCEANDSINK | Chauffage retour 7
Port_991317_0 | SOURCEANDSINK | Chauffage retour 7
Port_988011_0 | SOURCEANDSINK | Chauffage retour 10
Port_988034_2 | SOURCEANDSINK | Chauffage retour 10
Port_988011_1 | SOURCEANDSINK | Chauffage retour 10
Port_988036_2 | SOURCEANDSINK | Chauffage retour 10
Port_988024_1 | SOURCEANDSINK | Chauffage retour 10
Port_988036_1 | SOURCEANDSINK | Chauffage retour 10
Port_988030_0 | SOURCEANDSINK | Chauffage retour 10
Port_988032_1 | SOURCEANDSINK | Chauffage retour 10
Port_988030_1 | SOURCEANDSINK | Chauffage retour 10
Port_988032_2 | SOURCEANDSINK | Chauffage retour 10
Port_988034_1 | SOURCEANDSINK | Chauffage retour 10
Port_989356_1 | SOURCEANDSINK | Chauffage retour 10
Port_989369_1 | SOURCEANDSINK | Chauffage retour 10
Port_991309_1 | SOURCEANDSINK | Chauffage retour 7
Port_991309_2 | SOURCEANDSINK | Chauffage retour 7
Port_991317_1 | SOURCEANDSINK | Chauffage retour 7
InPort_991944_1 | SINK | Chauffage aller 5
OutPort_991940_1 | SOURCE | Chauffage aller 5
InPort_991941_0 | SINK | Chauffage aller 5
OutPort_991944_2 | SOURCE | Chauffage aller 5
OutPort_991941_1 | SOURCE | Chauffage aller 5
InPort_992128_1 | SINK | Chauffage retour 11
OutPort_992170_1 | SOURCE | Chauffage retour 11
InPort_992170_2 | SINK | Chauffage retour 11
OutPort_992168_0 | SOURCE | Chauffage retour 11
InPort_992168_1 | SINK | Chauffage retour 11
InPort_992325_0 | SINK | Eaux Usées 1
OutPort_993360_2 | SOURCE | Eaux Usées 1
OutPort_992325_1 | SOURCE | Eaux Usées 1
InPort_993150_1 | SINK | Chauffage retour 10
OutPort_993291_2 | SOURCE | Chauffage retour 10
InPort_993289_1 | SINK | Chauffage retour 10
OutPort_993151_0 | SOURCE | Chauffage retour 10
InPort_993360_1 | SINK | Eaux Usées 1
OutPort_993151_1 | SOURCE | Eaux Usées 1
InPort_993291_1 | SINK | Chauffage retour 10
OutPort_993289_2 | SOURCE | Chauffage retour 10

# IfcDoor: HM-Double:1460 x 2040 mm, HM-Double:1460 x 2040 mm:714456
In: Niveau 0
Type - OperationType: DOUBLE_DOOR_SINGLE_SWING; ParameterTakesPrecedence: no; Sizeable: no; Material: RAL1013-Blanc perle, RAL1002-Jaune sable
Type - HM-Double:1460 x 2040 mm:714456:1 - PanelOperation: SWINGING
Type - Pset_DoorCommon - IsExternal: no
OverallHeight: 2041.5 mm; OverallWidth: 1463 mm
Pset_DoorCommon - Reference: 1460 x 2040 mm
Pset_QuantityTakeOff - Reference: 1460 x 2040 mm

# IfcEnergyConversionDevice: HC_Boiler_MEPcontent_Vaillant_VPS_R_Heating_Cooling_DE-DE:uniSTOR VPS R 100/1, HC_Boiler_MEPcontent_Vaillant_VPS_R_Heating_Cooling_DE-DE:uniSTOR VPS R 100/1:931176
In: Niveau 0
Type - Material: Color RGB 219-227-229, Color RGB 040-040-040, Color RGB 111-106-099, <Unnamed>
Type - Pset_ManufacturerTypeInformation - Manufacturer: Vaillant
Pset_DistributionFlowElementCommon - Reference: uniSTOR VPS R 100/1; sets with these values: 2
Group: Chauffage aller 1; Chauffage retour 5; Chauffage retour 6; Chauffage retour 9

# IfcFlowController: Clapet anti-retour DN40:1 1/2'' (5)
In: Niveau 0
Type - PredefinedType: REGULATING; Material: Color RGB 202-154-058, Color RGB 044-044-044, Color RGB 195-195-195
Type - Pset_DuctConnection - ConnectionType: Gas ISO 228/1
Type - Pset_ManufacturerTypeInformation - Manufacturer: Caleffi Italy
Type - Pset_PipeConnection - ConnectionType: Gas ISO 228/1
Material: Color RGB 202-154-058
Pset_DistributionFlowElementCommon - Reference: 1 1/2''; sets with these values: 2
Name (Clapet anti-retour DN40:1 1/2'':...) | Group
877776 | Chauffage aller 8
877798 | Chauffage aller 4
877814 | Chauffage aller 10
877834 | Chauffage aller 11
981548 | Chauffage aller 1

# IfcFlowController: Gaz naturel - Electrovanne gaz:DN 32, Gaz naturel - Electrovanne gaz:DN 32:991309
In: Niveau 0
Type - Material: Métal
Pset_DistributionFlowElementCommon - Reference: DN 32; sets with these values: 2
Group: Chauffage retour 7

# IfcFlowController: Gaz naturel - Vanne isolement:DN 10, Gaz naturel - Vanne isolement:DN 10:989356
In: Niveau 0
Type - Material: Métal corps, Jaune Manche
Pset_DistributionFlowElementCommon - Reference: DN 10; sets with these values: 2
Group: Chauffage retour 10

# IfcFlowController: Gaz naturel - Volume tampon:100 L, Gaz naturel - Volume tampon:100 L:984671
In: Niveau 1
Type - Material: Jaune ALU, <Unnamed>
Pset_DistributionFlowElementCommon - Reference: 100 L; sets with these values: 2
Group: Chauffage retour 10

# IfcFlowController: Grundfos_MAGNA3_Single Head_40:THIS IS A TYPE CATALOG FAMILY, Grundfos_MAGNA3_Single Head_40:THIS IS A TYPE CATALOG FAMILY:981415
In: Niveau 0
Type - Material: Color RGB 042-042-042, Color RGB 137-029-029, Color RGB 255-255-255, Color RGB 022-211-117, Color RGB 079-079-079, Color RGB 165-165-165
Type - Pset_ElectricalDeviceCommon - NominalCurrent: 0.8 A
Type - Pset_ManufacturerTypeInformation - Manufacturer: Grundfos
Pset_DistributionFlowElementCommon - Reference: THIS IS A TYPE CATALOG FAMILY; sets with these values: 2
Group: Chauffage aller 1

# IfcFlowController: HVAC_Boilers_Viessmann_Vitocrossal-300-80kW:Standard, HVAC_Boilers_Viessmann_Vitocrossal-300-80kW:Standard:913983
In: Niveau 0
Type - Material: <Unnamed>
Type - Pset_ManufacturerTypeInformation - Manufacturer: Viessmann
Pset_DistributionFlowElementCommon - Reference: Standard; sets with these values: 2
Group: Chauffage aller 1; Chauffage retour 10; Chauffage retour 6

# IfcFlowController: M_Valve_Ball_MEPcontent_Caleffi_3230 DN25:1'', M_Valve_Ball_MEPcontent_Caleffi_3230 DN25:1'':937416
In: Niveau 0
Type - PredefinedType: REGULATING; Material: Color RGB 044-044-044, Color RGB 202-154-058
Type - Pset_DuctConnection - ConnectionType: Gas ISO 228/1
Type - Pset_ManufacturerTypeInformation - Manufacturer: Caleffi Italy
Type - Pset_PipeConnection - ConnectionType: Gas ISO 228/1
Pset_DistributionFlowElementCommon - Reference: 1''; sets with these values: 2
Group: Autre 1

# IfcFlowController: M_Valve_Ball_MEPcontent_Caleffi_3230 DN40:1 1/2'' (8)
In: Niveau 0
Type - PredefinedType: REGULATING; Material: Color RGB 202-154-058, Color RGB 044-044-044, Color RGB 195-195-195
Type - Pset_DuctConnection - ConnectionType: Gas ISO 228/1
Type - Pset_ManufacturerTypeInformation - Manufacturer: Caleffi Italy
Type - Pset_PipeConnection - ConnectionType: Gas ISO 228/1
Material: Color RGB 044-044-044, Color RGB 202-154-058
Pset_DistributionFlowElementCommon - Reference: 1 1/2''; sets with these values: 2
Name (M_Valve_Ball_MEPcontent_Caleffi_3230 DN40:1 1/2'':...) | Group
800542 | Chauffage aller 12
800556 | Chauffage aller 4
800572 | Chauffage aller 13
800588 | Chauffage aller 8
800612 | Chauffage aller 14
800628 | Chauffage aller 10
800652 | Chauffage aller 2
800673 | Chauffage aller 11

# IfcFlowController: M_Valve_Ball_MEPcontent_Caleffi_3230 DN50:2'' (2)
In: Niveau 0
Type - PredefinedType: REGULATING; Material: Color RGB 044-044-044, Color RGB 202-154-058, Color RGB 195-195-195
Type - Pset_DuctConnection - ConnectionType: Gas ISO 228/1
Type - Pset_ManufacturerTypeInformation - Manufacturer: Caleffi Italy
Type - Pset_PipeConnection - ConnectionType: Gas ISO 228/1
Material: Color RGB 044-044-044, Color RGB 202-154-058
Pset_DistributionFlowElementCommon - Reference: 2''; sets with these values: 2
Name (M_Valve_Ball_MEPcontent_Caleffi_3230 DN50:2'':...) | Group
812960 | Chauffage retour 1
813000 | Chauffage aller 1

# IfcFlowController: M_Valve_Ball_MEPcontent_Caleffi_638 DN32_Three-way:1 1/4'' 230V L, M_Valve_Ball_MEPcontent_Caleffi_638 DN32_Three-way:1 1/4'' 230V L:932503
In: Niveau 0
Type - PredefinedType: REGULATING; Material: Color RGB 201-201-201, Color RGB 045-045-045, Color RGB 202-154-058
Type - Pset_DuctConnection - ConnectionType: Gas ISO 228/1 (Bottom) - EN 10226-1 (Lateral)
Type - Pset_ManufacturerTypeInformation - Manufacturer: Caleffi Italy
Type - Pset_PipeConnection - ConnectionType: Gas ISO 228/1 (Bottom) - EN 10226-1 (Lateral)
Pset_DistributionFlowElementCommon - Reference: 1 1/4'' 230V L; sets with these values: 2
Group: Chauffage retour 6

# IfcFlowController: M_Valve_Ball_MEPcontent_Caleffi_638 DN40_Three-way:1 1/2'' 230V L (2)
In: Niveau 0
Type - PredefinedType: REGULATING; Material: Color RGB 201-201-201, Color RGB 045-045-045, Color RGB 202-154-058
Type - Pset_DuctConnection - ConnectionType: Gas ISO 228/1 (Bottom) - EN 10226-1 (Lateral)
Type - Pset_ManufacturerTypeInformation - Manufacturer: Caleffi Italy
Type - Pset_PipeConnection - ConnectionType: Gas ISO 228/1 (Bottom) - EN 10226-1 (Lateral)
Pset_DistributionFlowElementCommon - Reference: 1 1/2'' 230V L; sets with these values: 2
Name (M_Valve_Ball_MEPcontent_Caleffi_638 DN40_Three-way:1 1/2'' 230V L:...) | Group
784664 | Chauffage aller 4
788127 | Chauffage aller 8

# IfcFlowController: Pompe grundfoss Double:THIS IS A TYPE CATALOG FAMILY (3)
In: Niveau 0
Type - Material: Color RGB 042-042-042, Color RGB 255-255-255, Color RGB 022-211-117, Color RGB 165-165-165, Color RGB 137-029-029, Color RGB 195-195-195, Color RGB 079-079-079
Type - Pset_ElectricalDeviceCommon - NominalCurrent: 1.56 A; NumberOfPoles: 1
Type - Pset_ManufacturerTypeInformation - Manufacturer: Grundfos
Pset_DistributionFlowElementCommon - Reference: THIS IS A TYPE CATALOG FAMILY; sets with these values: 2
Name (Pompe grundfoss Double:THIS IS A TYPE CATALOG FAMILY:...) | Group
761970 | Chauffage aller 4
788118 | Chauffage aller 8
788332 | Chauffage aller 9

# IfcFlowController: Pompe grundfoss Double:THIS IS A TYPE CATALOG FAMILY, Pompe grundfoss Double:THIS IS A TYPE CATALOG FAMILY:788391
In: Niveau 0
Type - Material: Color RGB 042-042-042, Color RGB 255-255-255, Color RGB 022-211-117, Color RGB 165-165-165, Color RGB 137-029-029, Color RGB 195-195-195, Color RGB 079-079-079
Type - Pset_ElectricalDeviceCommon - NumberOfPoles: 1; NominalCurrent: 1.56 A
Type - Pset_ManufacturerTypeInformation - Manufacturer: Grundfos
Pset_DistributionFlowElementCommon - Reference: THIS IS A TYPE CATALOG FAMILY; sets with these values: 2
Group: Chauffage aller 2

# IfcFlowController: Pompe simple DN32:THIS IS A TYPE CATALOG FAMILY, Pompe simple DN32:THIS IS A TYPE CATALOG FAMILY:853877
In: Niveau 0
Type - Material: Color RGB 255-255-255, Color RGB 042-042-042, yellow, Color RGB 137-029-029, Color RGB 022-211-117, Color RGB 079-079-079, Color RGB 165-165-165
Type - Pset_ElectricalDeviceCommon - NominalCurrent: 0.56 A
Type - Pset_ManufacturerTypeInformation - Manufacturer: Grundfos
Pset_DistributionFlowElementCommon - Reference: THIS IS A TYPE CATALOG FAMILY; sets with these values: 2
Group: Chauffage aller 20

# IfcFlowController: Sonde de température:1 1/2'' (2)
In: Niveau 0
Type - PredefinedType: REGULATING; Material: Color RGB 202-154-058, Color RGB 044-044-044, Color RGB 195-195-195
Type - Pset_DuctConnection - ConnectionType: Gas ISO 228/1
Type - Pset_ManufacturerTypeInformation - Manufacturer: Caleffi Italy
Type - Pset_PipeConnection - ConnectionType: Gas ISO 228/1
Material: Color RGB 202-154-058, Couleur d'équipements2, <Unnamed>
Pset_DistributionFlowElementCommon - Reference: 1 1/2''; sets with these values: 2
Name (Sonde de température:1 1/2'':...) | Group
880787 | Chauffage aller 12
880819 | Chauffage aller 13

# IfcFlowController: Vanne Mitigeuse DN40:40 mm, Vanne Mitigeuse DN40:40 mm:836287
In: Niveau 0
Type - Material: <Unnamed>, Couleur équipements
Pset_DistributionFlowElementCommon - Reference: 40 mm; sets with these values: 2
Group: Chauffage aller 16; Chauffage aller 18

# IfcFlowFitting: Coude - Générique:Standard (71)
Type - Material: <Unnamed>
Pset_DistributionFlowElementCommon - Reference: Standard; sets with these values: 2
Name (Coude - Générique:Standard:...) | In | Group
731204 | Niveau 0 | Chauffage aller 4
731210 | Niveau 0 | Chauffage aller 4
731466 | Niveau 0 | Chauffage aller 2
731492 | Niveau 0 | Chauffage aller 11
731651 | Niveau 0 | Chauffage aller 13
731653 | Niveau 0 | Chauffage aller 13
731695 | Niveau 0 | Chauffage aller 8
731697 | Niveau 0 | Chauffage aller 8
731759 | Niveau 0 | Chauffage aller 14
731761 | Niveau 0 | Chauffage aller 14
731843 | Niveau 0 | Chauffage aller 10
731845 | Niveau 0 | Chauffage aller 10
732496 | Niveau 0 | Chauffage aller 2
732698 | Niveau 0 | Chauffage aller 12
732700 | Niveau 0 | Chauffage aller 12
734948 | Niveau 0 | Chauffage aller 2
734986 | Niveau 0 | Chauffage aller 16
777958 | Niveau 0 | Chauffage aller 12
784621 | Niveau 0 | Chauffage aller 4
788230 | Niveau 0 | Chauffage aller 8
788303 | Niveau 0 | Chauffage aller 13
788510 | Niveau 0 | Chauffage aller 14
789825 | Niveau 0 | Chauffage aller 2
789916 | Niveau 0 | Autre 1
791255 | Niveau 0 | Chauffage aller 10
791313 | Niveau 0 | Chauffage aller 11
809786 | Niveau 0 | Chauffage retour 2
809790 | Niveau 0 | Chauffage retour 2; Chauffage aller 11
824275 | Niveau 0 | Chauffage aller 16; Chauffage retour 4
824307 | Niveau 0 | Eau Froide Sanitaire 1
824453 | Niveau 0 | Chauffage aller 18
824502 | Niveau 0 | Chauffage aller 18
824805 | Niveau 0 | Chauffage aller 18
825222 | Niveau 0 | Chauffage aller 17
825249 | Niveau 0 | Chauffage aller 2
831752 | Niveau 0 | Chauffage aller 17
831797 | Niveau 0 | Chauffage aller 17
836610 | Niveau 0 | Chauffage aller 16
836668 | Niveau 0 | Chauffage aller 16
836702 | Niveau 0 | Chauffage aller 16
836860 | Niveau 0 | Chauffage aller 16
836927 | Niveau 0 | Chauffage aller 16
836937 | Niveau 0 | Chauffage aller 16
853764 | Niveau 0 | Chauffage aller 2
869536 | Niveau 0 | Autre 1
872736 | Niveau 0 | Eaux Usées 2
918360 | Niveau 0 | Chauffage aller 1
918364 | Niveau 0 | Chauffage aller 1
931903 | Niveau 0 | Chauffage aller 1
931907 | Niveau 0 | Chauffage aller 1
931927 | Niveau 0 | Chauffage aller 1
932036 | Niveau 0 | Chauffage retour 5
932181 | Niveau 0 | Chauffage retour 5
932233 | Niveau 0 | Chauffage retour 5
933277 | Niveau 0 | Chauffage retour 8
933415 | Niveau 0 | Chauffage aller 1
933678 | Niveau 0 | Chauffage aller 3; Chauffage retour 9
933682 | Niveau 0 | Chauffage retour 9
933686 | Niveau 0 | Chauffage retour 9
934110 | Niveau 0 | Autre 1
934114 | Niveau 0 | Autre 1
937511 | Niveau 0 | Chauffage retour 6
985191 | Niveau 1 | Chauffage retour 10
985195 | Niveau 0 | Chauffage retour 10
985199 | Niveau 0 | Chauffage retour 10
988032 | Niveau 0 | Chauffage retour 10
988036 | Niveau 1 | Chauffage retour 10
991944 | Niveau 0 | Chauffage aller 5
992170 | Niveau 0 | Chauffage retour 11
993289 | Niveau 0 | Chauffage retour 10
993360 | Niveau 0 | Eaux Usées 1

# IfcFlowFitting: Transformation - Générique:Standard (29)
Type - Material: <Unnamed>
Pset_DistributionFlowElementCommon - Reference: Standard; sets with these values: 2
Name (Transformation - Générique:Standard:...) | In | Group
732593 | Niveau 0 | Chauffage retour 2
734946 | Niveau 0 | Chauffage aller 2
734984 | Niveau 0 | Chauffage aller 16
824245 | Niveau 0 | Eau Froide Sanitaire 1
836824 | Niveau 0 | Chauffage aller 16
836971 | Niveau 0 | Chauffage aller 16
853629 | Niveau 0 | Chauffage aller 19
869441 | Niveau 0 | Chauffage retour 1
911631 | Niveau 0 | Chauffage aller 3
931925 | Niveau 0 | Chauffage aller 1
932230 | Niveau 0 | Chauffage retour 5
932235 | Niveau 0 | Chauffage retour 5
932395 | Niveau 0 | Chauffage retour 6
932529 | Niveau 0 | Chauffage retour 6
932532 | Niveau 0 | Chauffage retour 6
933294 | Niveau 0 | Chauffage aller 1; Chauffage retour 8
933412 | Niveau 0 | Chauffage aller 1
933680 | Niveau 0 | Chauffage aller 3
933688 | Niveau 0 | Chauffage retour 9
933796 | Niveau 0 | Chauffage retour 6
934051 | Niveau 0 | Autre 1
934116 | Niveau 0 | Autre 1
981419 | Niveau 0 | Chauffage aller 1
981421 | Niveau 0 | Chauffage aller 1
981578 | Niveau 0 | Chauffage aller 1
981580 | Niveau 0 | Chauffage aller 1
985193 | Niveau 1 | Chauffage retour 10
988034 | Niveau 0 | Chauffage retour 10
993291 | Niveau 0 | Chauffage retour 10

# IfcFlowFitting: Té - Générique:Standard (6)
In: Niveau 0
Type - Material: <Unnamed>
Pset_DistributionFlowElementCommon - Reference: Standard; sets with these values: 2
Name (Té - Générique:Standard:...) | Group
734538 | Chauffage retour 1
788062 | Chauffage aller 4
788134 | Chauffage aller 8
836876 | Chauffage aller 16
837166 | Chauffage aller 16
932846 | Chauffage aller 1

# IfcFlowSegment: Canalisation:Bride acier (85)
Pset_DistributionFlowElementCommon - Reference: Bride acier; sets with these values: 2
Pset_FlowSegmentDuctSegment - sets with these values: 2
Name (Canalisation:Bride acier:...) | In | Length (mm) | Group
730939 | Niveau 0 | 28.3751 | Chauffage aller 12
730962 | Niveau 0 | 3355.32 | Chauffage aller 12
731057 | Niveau 0 | 274 | Chauffage aller 12
731196 | Niveau 0 | 28.3751 | Chauffage aller 4
731198 | Niveau 0 | 70.1267 | Chauffage aller 4
731202 | Niveau 0 | 3336.97 | Chauffage aller 4
731208 | Niveau 0 | 374 | Chauffage aller 4
731294 | Niveau 0 | 28.3751 | Chauffage aller 13
731300 | Niveau 0 | 2793.71 | Chauffage aller 13
731318 | Niveau 0 | 28.3751 | Chauffage aller 8
731324 | Niveau 0 | 2736.97 | Chauffage aller 8
731340 | Niveau 0 | 28.3751 | Chauffage aller 10
731342 | Niveau 0 | 70.1267 | Chauffage aller 10
731346 | Niveau 0 | 2136.97 | Chauffage aller 10
731430 | Niveau 0 | 28.3751 | Chauffage aller 14
731436 | Niveau 0 | 2486.97 | Chauffage aller 14
731458 | Niveau 0 | 28.3751 | Chauffage aller 2
731460 | Niveau 0 | 51.4873 | Chauffage aller 2
731484 | Niveau 0 | 28.3751 | Chauffage aller 11
731486 | Niveau 0 | 25.1267 | Chauffage aller 11
731572 | Niveau 0 | 474 | Chauffage aller 13
731586 | Niveau 0 | 574 | Chauffage aller 8
731600 | Niveau 0 | 674 | Chauffage aller 14
731790 | Niveau 0 | 774 | Chauffage aller 10
732251 | Niveau 0 | 1666 | Chauffage aller 2
732428 | Niveau 0 | 669.405 | Chauffage aller 2
732518 | Niveau 0 | 742.975 | Chauffage retour 2
732634 | Niveau 0 | 85.4052 | Chauffage aller 11
734033 | Niveau 0 | 1076.25 | Chauffage aller 16
734276 | Niveau 0 | 65.1218 | Eau Froide Sanitaire 1; Chauffage retour 4
734887 | Niveau 0 | 790.975 | Chauffage aller 2
777889 | Niveau 0 | 217 | Chauffage aller 12
788063 | Niveau 0 | 537.41 | Chauffage aller 4
788116 | Niveau 0 | 70.1267 | Chauffage aller 8
788121 | Niveau 0 | 17 | Chauffage aller 13
788135 | Niveau 0 | 117 | Chauffage aller 8
788456 | Niveau 0 | 133.735 | Chauffage aller 14
789472 | Niveau 0 | 166.987 | Chauffage aller 4
800558 | Niveau 0 | 117 | Chauffage aller 4
800574 | Niveau 0 | 112.947 | Chauffage aller 13
800614 | Niveau 0 | 225.535 | Chauffage aller 14
800630 | Niveau 0 | 125.535 | Chauffage aller 10
800654 | Niveau 0 | 107.783 | Chauffage aller 2
800675 | Niveau 0 | 52.7825 | Chauffage aller 11
806821 | Niveau 0 | 1675 | Chauffage retour 2
824278 | Niveau 0 | 4.20718 | Eau Froide Sanitaire 1
824420 | Niveau 0 | 106.748 | Chauffage aller 18
824445 | Niveau 0 | 419.33 | Chauffage aller 18
824455 | Niveau 0 | 218.762 | Chauffage aller 18
824673 | Niveau 0 | 99.8761 | Chauffage aller 17
824677 | Niveau 0 | 2645.13 | Chauffage aller 17
824781 | Niveau 0 | 240.828 | Chauffage aller 2
825239 | Niveau 0 | 115.969 | Chauffage aller 2
825423 | Niveau 0 | 337.41 | Chauffage aller 8
831779 | Niveau 0 | 102.522 | Chauffage aller 17
836289 | Niveau 0 | 102.651 | Chauffage aller 18
836562 | Niveau 0 | 497.903 | Chauffage aller 16
836570 | Niveau 0 | 76.5898 | Chauffage aller 16
836608 | Niveau 0 | 425.014 | Chauffage aller 16
853978 | Niveau 0 | 140.604 | Chauffage aller 20
854038 | Niveau 0 | 82.7125 | Chauffage aller 20
877778 | Niveau 0 | 65.8598 | Chauffage aller 8
877800 | Niveau 0 | 65.8598 | Chauffage aller 4
877816 | Niveau 0 | 308.735 | Chauffage aller 10
877836 | Niveau 0 | 226.487 | Chauffage aller 11
880789 | Niveau 0 | 241.654 | Chauffage aller 12
880821 | Niveau 0 | 203.259 | Chauffage aller 13
918343 | Niveau 0 | 923.307 | Chauffage aller 1
918356 | Niveau 0 | 984.209 | Chauffage aller 1
918357 | Niveau 0 | 12.6332 | Chauffage aller 1
918368 | Niveau 0 | 709.177 | Chauffage aller 1
932373 | Niveau 0 | 83.7478 | Chauffage retour 6
932385 | Niveau 0 | 98.6498 | Chauffage retour 6
932527 | Niveau 0 | 1351.67 | Chauffage retour 6
932849 | Niveau 0 | 390.792 | Chauffage aller 1
933275 | Niveau 0 | 498.6 | Chauffage retour 8
985168 | Niveau 0 | 101.525 | Chauffage retour 10
985179 | Niveau 0 | 117.522 | Chauffage retour 10
985187 | Niveau 1 | 107.037 | Chauffage retour 10
985188 | Niveau 0 | 1850.6 | Chauffage retour 10
988011 | Niveau 1 | 677.312 | Chauffage retour 10
988024 | Niveau 1 | 1103.13 | Chauffage retour 10
988030 | Niveau 0 | 1375 | Chauffage retour 10
989369 | Niveau 0 | 116.242 | Chauffage retour 10
991317 | Niveau 0 | 243.618 | Chauffage retour 7

# IfcFlowSegment: Canalisation:Standard (47)
In: Niveau 0
Pset_DistributionFlowElementCommon - Reference: Standard; sets with these values: 2
Pset_FlowSegmentDuctSegment - sets with these values: 2
Name (Canalisation:Standard:...) | Length (mm) | Group
734457 | 677.767 | Autre 1
734536 | 284.006 | Autre 1
734539 | 355.207 | Chauffage retour 1
734875 | 547.506 | Chauffage aller 16
734972 | 334.063 | Chauffage aller 16
788051 | 369 | Chauffage aller 4
788132 | 369 | Chauffage aller 8
789420 | 145.463 | Chauffage aller 4
789541 | 166.987 | Chauffage aller 8
789702 | 115.127 | Chauffage aller 9
789725 | 115.127 | Chauffage aller 2
789910 | 104.515 | Autre 1; Chauffage retour 1
800544 | 112.947 | Chauffage aller 12
812962 | 168.38 | Chauffage retour 1
813002 | 179.467 | Chauffage aller 1
824020 | 192 | Chauffage aller 16
824640 | 1860.1 | Chauffage aller 15
825383 | 145.463 | Chauffage aller 8
836827 | 334.607 | Chauffage aller 16
836907 | 340.201 | Chauffage aller 16
836917 | 654.264 | Chauffage aller 16
837075 | 8067.24 | Chauffage aller 16
837131 | 3093 | Chauffage aller 16
837179 | 73.8697 | Chauffage aller 16
869520 | 62.4057 | Autre 1
911885 | 490.305 | Chauffage aller 3
931886 | 101.578 | Chauffage aller 1
931899 | 25.3997 | Chauffage aller 1
931900 | 81.7269 | Chauffage aller 1
931911 | 145.5 | Chauffage aller 1
932019 | 1255.36 | Chauffage retour 5
932032 | 25.3997 | Chauffage retour 5
932033 | 431.769 | Chauffage retour 5
932209 | 107.877 | Chauffage retour 5
932222 | 100.126 | Chauffage retour 5
933656 | 497.619 | Chauffage retour 9
933669 | 390.126 | Chauffage retour 9
933676 | 563.27 | Chauffage retour 9
981417 | 677.242 | Chauffage aller 1
981576 | 96.7871 | Chauffage aller 1
991940 | 25.3997 | Chauffage aller 5
991941 | 1709 | Chauffage aller 5
992128 | 25.3997 | Chauffage retour 11
992168 | 1569 | Chauffage retour 11
992325 | 461.088 | Eaux Usées 1
993150 | 110.245 | Chauffage retour 10
993151 | 92.95 | Chauffage retour 10; Eaux Usées 1

# IfcFlowTerminal: Grille Entrée d'air Chaufferie:THIS IS A TYPE CATALOG FAMILY (2)
Type - PredefinedType: GRILLE; Material: Color RGB 153-152-151, Color RGB 245-245-245, Color RGB 078-078-078
Type - Pset_ManufacturerTypeInformation - Manufacturer: Trox
Type - Pset_ProductRequirements - Category: DM_ARTICLE_AIRTERMINAL
Pset_DistributionFlowElementCommon - Reference: THIS IS A TYPE CATALOG FAMILY; sets with these values: 2
Name (Grille Entrée d'air Chaufferie:THIS IS A TYPE CATALOG FAMILY:...) | In
859315 | Niveau 0
869310 | Niveau 1

# IfcFlowTerminal: Lampadaire - Halogène:230V, Lampadaire - Halogène:230V:883311
In: Niveau 0
Type - Material: Acier, chromé, Verre, Givré
Type - Pset_LightFixtureTypeCommon - TotalWattage: 100 W
Classification: D5020230 Uniformat (Uniformat)
Pset_DistributionFlowElementCommon - Reference: 230V; sets with these values: 2

# IfcFlowTerminal: Siphon de sol - Rectangulaire:Filtre à tamis 125 mmx125 mm - Tuyau d'évacuation 50 mm, Siphon de sol - Rectangulaire:Filtre à tamis 125 mmx125 mm - Tuyau d'évacuation 50 mm:874839
In: Niveau 0
Type - Material: <Unnamed>
Pset_DistributionFlowElementCommon - Reference: Filtre à tamis 125 mmx125 mm - Tuyau d'évacuation 50 mm; sets with these values: 2

# IfcOpeningElement: Opening (3)
In: Niveau 0
Name | Reference | sets with these values
2 x Mur de base:Générique - 200 mm:398 | Générique - 200 mm | 2
HM-Double:1460 x 2040 mm:714456:1

# IfcRoof: Toit de base:Générique - 400 mm, Toit de base:Générique - 400 mm:710315
In: Niveau 0
Material: Contreplaqué, revêtement 400 mm
Pset_QuantityTakeOff - Reference: Générique - 400 mm
Pset_RoofCommon - IsExternal: yes; Reference: Générique - 400 mm; ProjectedArea: 47.0401 m2; TotalArea: 47.0401 m2

# IfcSlab: Sol:Générique 100 mm 2, Sol:Générique 100 mm 2:820925
In: Niveau 0
Type - PredefinedType: FLOOR; Material: Sol par défaut 100 mm
Type - Pset_SlabCommon - IsExternal: no
Pset_QuantityTakeOff - Reference: Générique 100 mm 2; sets with these values: 2
Pset_SlabCommon - LoadBearing: no; PitchAngle: 0 deg; Reference: Générique 100 mm 2

# IfcSlab: Sol:Générique 300 mm, Sol:Générique 300 mm:710304
In: Niveau 0
Type - PredefinedType: FLOOR; Material: Sol par défaut 300 mm
Type - Pset_SlabCommon - IsExternal: no
Pset_QuantityTakeOff - Reference: Générique 300 mm; sets with these values: 2
Pset_SlabCommon - LoadBearing: no; Reference: Générique 300 mm; PitchAngle: 0 deg

# IfcSlab: Toit de base:Générique - 400 mm, Toit de base:Générique - 400 mm:710315
In: Niveau 0
Type - PredefinedType: ROOF
Type - Pset_SlabCommon - IsExternal: yes; ThermalTransmittance: 0.265 kg/K/s3
Material: Contreplaqué, revêtement 400 mm
Pset_QuantityTakeOff - Reference: Générique - 400 mm; sets with these values: 2
Pset_SlabCommon - PitchAngle: 0 deg; Reference: Générique - 400 mm

# IfcWallStandardCase: Mur de base:Générique - 200 mm (4)
In: Niveau 0
Type - PredefinedType: STANDARD; Material: Mur par défaut 200 mm
Type - Pset_WallCommon - IsExternal: yes
Pset_QuantityTakeOff - Reference: Générique - 200 mm; sets with these values: 2
Pset_WallCommon - Reference: Générique - 200 mm; ExtendToStructure: no; LoadBearing: no
Name (Mur de base:Générique - 200 mm:...)
710118
710193
710238
710279
